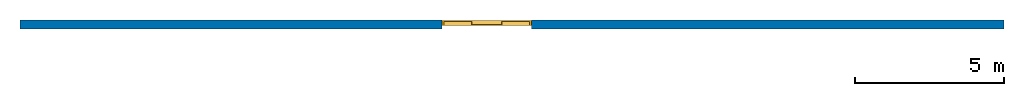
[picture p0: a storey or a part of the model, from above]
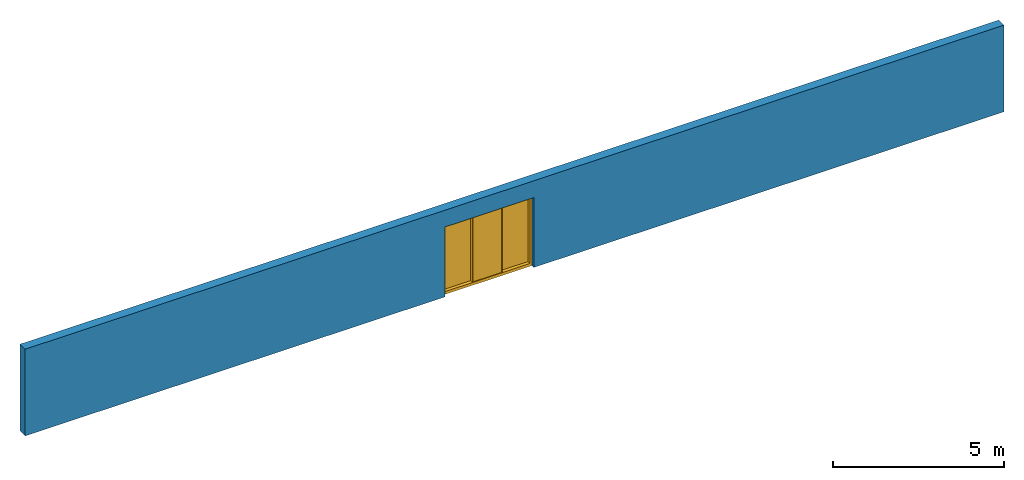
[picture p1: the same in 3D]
Properties of the parts of a building model (IFC2X3)

# File
Description: ViewDefinition [CoordinationView]
File name: Numero del progetto
Time: 2017-06-27T17:38:46
Written by: The EXPRESS Data Manager Version 5.01.0100.02.64mod : 6 Jun 2012
Made in: 20130308_1515(x64) - Exporter 2014.0.2013.0308 - Default UI
Comment: STEP Physical File produced by: The EXPRESS Data Manager Version 5.01.0100.02.64mod : 6 Jun 2012 * Module: EDMstepFileFactory/EDMstandAlone * Creation date: Tue Jun 27 17:38:46 2017 * Host: DELLATORRE-HP * Database: C:\Users\ILRAIA~1\AppData\Local\Temp\{69380BD8-A0E5-49FD-9C31-83FE6529C273}\ifc * Database version: 5507 * Database creation date: Tue Jun 27 17:38:44 2017 * Schema: IFC2X3 * Model: DataRepository.ifc * Model creation date: Tue Jun 27 17:38:44 2017 * Header model: DataRepository.ifc_HeaderModel * Header model creation date: Tue Jun 27 17:38:44 2017 * EDMuser: sdai-user * EDMgroup: sdai-group * License ID and type: 5605 : Permanent license. Expiry date: * EDMstepFileFactory options: 020000

# IfcProject, Numero del progetto
LongName: Nome; Phase: Stato del progetto

# IfcSite, Default
RefLatitude: 41, 47, 59, 997253; RefLongitude: 12, 36, 0, 1373; RefElevation: 0 m

# IfcBuilding
Pset_BuildingCommon - NumberOfStoreys: 1
Altro - Stato del progetto: Stato del progetto; Nome del cliente: proprietario; Nome del progetto: Nome; Data di consegna del progetto: Data di consegna; Numero del progetto: Numero del progetto

# IfcBuildingStorey, 0 - Piano Terra
LongName: 0 - Piano Terra; Elevation: 0 m
Vincoli - Base quota altimetrica: Punto base progetto; Prospetto: 0 m
Grafica - Spessore di linea: 1; Simbolo: Estremità Livello: Triangolo; Simbolo a estremità 1 per default: no; Colore: 0; Modello di linea: Tratto; Simbolo a estremità 2 per default: yes
Dati identità - Nome: 0 - Piano Terra; Strutturale: no; Piano edificio: yes
Dimensioni - Altezza di calcolo: 0 m

# IfcWallStandardCase: Muro di base:Generico - 30 cm, Muro di base:Generico - 30 cm:95129
In: 0 - Piano Terra
Type - PredefinedType: STANDARD; Material: Default - Muro 0.3 m
Type - Dati identità - Nota chiave: Mb/3
Type - Costruzione - Larghezza: 0.3 m; Ripiegatura agli inserti: Non ripiegare; Ripiegatura alle estremità: Nessuno; Funzione: Esterno
Type - Proprietà analitiche - Assorbimento: 0.7; Ruvidità: 3
Type - Grafica - Colore del retino a dettaglio basso: 0
Type - Materiali e finiture - Materiale strutturale: Default - Muro
Dimensioni - Volume: 28.533 m3; Area: 95.11 m2; Lunghezza: 33.1 m
Vincoli - Delimita il locale: yes; Vincolo di altezza: Livello: 1 - Piano Primo; Distanza estensione altezza: 0 m; Distanza estensione base: 0 m; Offset altezza: 0 m; Offset base: 0 m; Linea di ubicazione: Linea d'asse del muro; L'altezza è associata: no; Altezza non collegata: 3.1 m; La base è associata: no; Vincolo di base: Livello: 0 - Piano Terra; Relativo a massa: no
Fasi - Fase di creazione: Stato di Progetto
Strutturale - Strutturale: no; Utilizzo strutturale: Non portante; Attiva modello analitico: no
Pset_WallCommon - Reference: Generico - 30 cm; LoadBearing: no; ExtendToStructure: no; IsExternal: yes

# IfcWindow: 2 ante scorrevoli + 1 anta fissa, Aluk_Infinium_3 ante:2 ante scorrevoli + 1 anta fissa:98709
In: 0 - Piano Terra
Type - ParameterTakesPrecedence: no; Sizeable: no; Material: Aluk (IT), Vetro
OverallHeight: 2.5 m; OverallWidth: 3 m
Vincoli - Altezza soglia: 0 m; Livello: Livello: 0 - Piano Terra; Altezza massima: 3.5 m; Visibilità altezza massima: no; Larghezza massima: 9 m; Visibilità larghezza massima: no
Altro - Altezza estremità: 2.5 m; Altezza di default del davanzale: 0 m
Dimensioni - offset filo muro ext: 0.015 m; aria TOP: 0 m; aria DX: 0 m; aria SX: 0 m; Larghezza: 3 m; Altezza: 2.5 m
Fasi - Fase di creazione: Stato di Progetto
Dati identità - Contrassegno: 1; URL: http://infinium.aluk.com/it#!/cover; Titolo OmniClass: Windows; Contrassegno tipo: 28; Produttore: Aluk (IT); Numero OmniClass: 23.30.20.00
Pset_ManufacturerTypeInformation - Manufacturer: Aluk (IT)
Pset_WindowCommon - Reference: 2 ante scorrevoli + 1 anta fissa; IsExternal: yes
Proprietà analitiche - Costruzione analitica: <Nessuno>
Costruzione - Chiusura muro: Per host
Materiali e finiture - Vetro: Vetro; Simboli: Simboli; Telaio: Aluk (IT)
Visibilità - ERRORE: no
